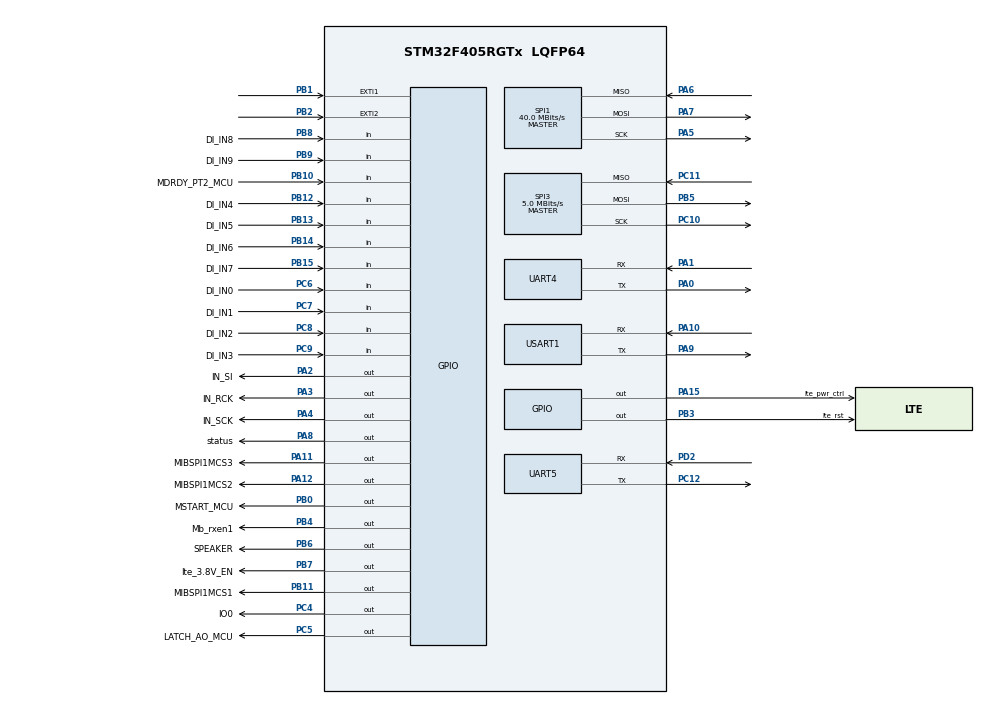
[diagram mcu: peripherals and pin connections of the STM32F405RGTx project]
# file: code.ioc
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Dma.Request0=UART4_RX
Dma.Request1=UART5_RX
Dma.Request2=USART1_RX
Dma.UART4_RX.0.Direction=DMA_PERIPH_TO_MEMORY
Dma.UART4_RX.0.FIFOMode=DMA_FIFOMODE_DISABLE
Dma.UART4_RX.0.Instance=DMA1_Stream2
Dma.UART4_RX.0.MemDataAlignment=DMA_MDATAALIGN_BYTE
Dma.UART4_RX.0.MemInc=DMA_MINC_ENABLE
Dma.UART4_RX.0.Mode=DMA_NORMAL
Dma.UART4_RX.0.PeriphDataAlignment=DMA_PDATAALIGN_BYTE
Dma.UART4_RX.0.PeriphInc=DMA_PINC_DISABLE
Dma.UART4_RX.0.Priority=DMA_PRIORITY_LOW
Dma.UART5_RX.1.Direction=DMA_PERIPH_TO_MEMORY
Dma.UART5_RX.1.FIFOMode=DMA_FIFOMODE_DISABLE
Dma.UART5_RX.1.Instance=DMA1_Stream0
Dma.UART5_RX.1.MemDataAlignment=DMA_MDATAALIGN_BYTE
Dma.UART5_RX.1.MemInc=DMA_MINC_ENABLE
Dma.UART5_RX.1.Mode=DMA_NORMAL
Dma.UART5_RX.1.PeriphDataAlignment=DMA_PDATAALIGN_BYTE
Dma.UART5_RX.1.PeriphInc=DMA_PINC_DISABLE
Dma.UART5_RX.1.Priority=DMA_PRIORITY_LOW
Dma.USART1_RX.2.Direction=DMA_PERIPH_TO_MEMORY
Dma.USART1_RX.2.FIFOMode=DMA_FIFOMODE_DISABLE
Dma.USART1_RX.2.Instance=DMA2_Stream2
Dma.USART1_RX.2.MemDataAlignment=DMA_MDATAALIGN_BYTE
Dma.USART1_RX.2.MemInc=DMA_MINC_ENABLE
Dma.USART1_RX.2.Mode=DMA_NORMAL
Dma.USART1_RX.2.PeriphDataAlignment=DMA_PDATAALIGN_BYTE
Dma.USART1_RX.2.PeriphInc=DMA_PINC_DISABLE
Dma.USART1_RX.2.Priority=DMA_PRIORITY_LOW
IWDG.Prescaler=IWDG_PRESCALER_256
IWDG.Reload=125
Mcu.Family=STM32F4
Mcu.Name=STM32F405RGTx
Mcu.Package=LQFP64
NVIC.DMA1_Stream0_IRQn=true\:0\:0\:false\:false\:true\:false\:true\:true
NVIC.DMA1_Stream2_IRQn=true\:0\:0\:false\:false\:true\:false\:true\:true
NVIC.DMA2_Stream2_IRQn=true\:0\:0\:false\:false\:true\:false\:true\:true
NVIC.EXTI1_IRQn=true\:0\:0\:false\:false\:true\:true\:true\:true
NVIC.EXTI2_IRQn=true\:0\:0\:false\:false\:true\:true\:true\:true
NVIC.PriorityGroup=NVIC_PRIORITYGROUP_4
NVIC.UART4_IRQn=true\:0\:0\:false\:false\:true\:true\:true\:true
NVIC.UART5_IRQn=true\:0\:0\:false\:false\:true\:true\:true\:true
NVIC.USART1_IRQn=true\:0\:0\:false\:false\:true\:true\:true\:true
PA0-WKUP.Mode=Asynchronous
PA0-WKUP.Signal=UART4_TX
PA1.Mode=Asynchronous
PA1.Signal=UART4_RX
PA10.Mode=Asynchronous
PA10.Signal=USART1_RX
PA11.GPIO_Label=MIBSPI1MCS3
PA11.Signal=GPIO_Output
PA12.GPIO_Label=MIBSPI1MCS2
PA12.Signal=GPIO_Output
PA13.Mode=Serial_Wire
PA13.Signal=SYS_JTMS-SWDIO
PA14.Mode=Serial_Wire
PA14.Signal=SYS_JTCK-SWCLK
PA15.GPIO_Label=lte_pwr_ctrl
PA15.Signal=GPIO_Output
PA2.GPIO_Label=IN_SI
PA2.Signal=GPIO_Output
PA3.GPIO_Label=IN_RCK
PA3.Signal=GPIO_Output
PA4.GPIO_Label=IN_SCK
PA4.Signal=GPIO_Output
PA5.Mode=Full_Duplex_Master
PA5.Signal=SPI1_SCK
PA6.Mode=Full_Duplex_Master
PA6.Signal=SPI1_MISO
PA7.Mode=Full_Duplex_Master
PA7.Signal=SPI1_MOSI
PA8.GPIO_Label=status
PA8.Signal=GPIO_Output
PA9.Mode=Asynchronous
PA9.Signal=USART1_TX
PB0.GPIO_Label=MSTART_MCU
PB0.Signal=GPIO_Output
PB1.GPIO_ModeDefaultEXTI=GPIO_MODE_IT_FALLING
PB1.GPIO_PuPd=GPIO_PULLUP
PB1.Signal=GPXTI1
PB10.GPIO_Label=MDRDY_PT2_MCU
PB10.Signal=GPIO_Input
PB11.GPIO_Label=MIBSPI1MCS1
PB11.GPIO_PuPd=GPIO_PULLUP
PB11.PinState=GPIO_PIN_SET
PB11.Signal=GPIO_Output
PB12.GPIO_Label=DI_IN4
PB12.Signal=GPIO_Input
PB13.GPIO_Label=DI_IN5
PB13.Signal=GPIO_Input
PB14.GPIO_Label=DI_IN6
PB14.Signal=GPIO_Input
PB15.GPIO_Label=DI_IN7
PB15.Signal=GPIO_Input
PB2.GPIO_ModeDefaultEXTI=GPIO_MODE_IT_FALLING
PB2.GPIO_PuPd=GPIO_PULLUP
PB2.Signal=GPXTI2
PB3.GPIO_Label=lte_rst
PB3.Signal=GPIO_Output
PB4.GPIO_Label=Mb_rxen1
PB4.Signal=GPIO_Output
PB5.Mode=Full_Duplex_Master
PB5.Signal=SPI3_MOSI
PB6.GPIO_Label=SPEAKER
PB6.Signal=GPIO_Output
PB7.GPIO_Label=lte_3.8V_EN
PB7.Signal=GPIO_Output
PB8.GPIO_Label=DI_IN8
PB8.Signal=GPIO_Input
PB9.GPIO_Label=DI_IN9
PB9.Signal=GPIO_Input
PC10.Mode=Full_Duplex_Master
PC10.Signal=SPI3_SCK
PC11.Mode=Full_Duplex_Master
PC11.Signal=SPI3_MISO
PC12.Mode=Asynchronous
PC12.Signal=UART5_TX
PC4.GPIO_Label=IO0
PC4.Signal=GPIO_Output
PC5.GPIO_Label=LATCH_AO_MCU
PC5.Signal=GPIO_Output
PC6.GPIO_Label=DI_IN0
PC6.Signal=GPIO_Input
PC7.GPIO_Label=DI_IN1
PC7.Signal=GPIO_Input
PC8.GPIO_Label=DI_IN2
PC8.Signal=GPIO_Input
PC9.GPIO_Label=DI_IN3
PC9.Signal=GPIO_Input
PD2.Mode=Asynchronous
PD2.Signal=UART5_RX
PH0-OSC_IN.Mode=HSE-External-Oscillator
PH0-OSC_IN.Signal=RCC_OSC_IN
PH1-OSC_OUT.Mode=HSE-External-Oscillator
PH1-OSC_OUT.Signal=RCC_OSC_OUT
ProjectManager.HeapSize=0x200
ProjectManager.StackSize=0x400
ProjectManager.TargetToolchain=MDK-ARM V5
RCC.48MHZClocksFreq_Value=40000000
RCC.AHBFreq_Value=80000000
RCC.APB1CLKDivider=RCC_HCLK_DIV2
RCC.APB1Freq_Value=40000000
RCC.APB1TimFreq_Value=80000000
RCC.APB2Freq_Value=80000000
RCC.APB2TimFreq_Value=80000000
RCC.CortexFreq_Value=80000000
RCC.HCLKFreq_Value=80000000
RCC.HSE_VALUE=8000000
RCC.HSI_VALUE=16000000
RCC.LSE_VALUE=32768
RCC.PLLM=4
RCC.PLLN=80
RCC.PLLSourceVirtual=RCC_PLLSOURCE_HSE
RCC.SYSCLKFreq_VALUE=80000000
RCC.SYSCLKSource=RCC_SYSCLKSOURCE_PLLCLK
RCC.VCOOutputFreq_Value=160000000
SPI1.BaudRatePrescaler=SPI_BAUDRATEPRESCALER_2
SPI1.CalculateBaudRate=40.0 MBits/s
SPI1.Direction=SPI_DIRECTION_2LINES
SPI1.Mode=SPI_MODE_MASTER
SPI1.VirtualType=VM_MASTER
SPI3.BaudRatePrescaler=SPI_BAUDRATEPRESCALER_8
SPI3.CalculateBaudRate=5.0 MBits/s
SPI3.Direction=SPI_DIRECTION_2LINES
SPI3.Mode=SPI_MODE_MASTER
SPI3.VirtualType=VM_MASTER
UART4.VirtualMode=Asynchronous
UART5.VirtualMode=Asynchronous
USART1.VirtualMode=VM_ASYNC
VP_IWDG_VS_IWDG.Mode=IWDG_Activate
board=custom

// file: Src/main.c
/* USER CODE BEGIN Header */
/**
  ******************************************************************************
  * @file           : main.c
  * @brief          : Main program body
  ******************************************************************************
  * @attention
  *
  * <h2><center>&copy; Copyright (c) 2023 STMicroelectronics.
  * All rights reserved.</center></h2>
  *
  * This software component is licensed by ST under BSD 3-Clause license,
  * the "License"; You may not use this file except in compliance with the
  * License. You may obtain a copy of the License at:
  *                        opensource.org/licenses/BSD-3-Clause
  *
  ******************************************************************************
  */
/* USER CODE END Header */
#include "main.h"

/* USER CODE BEGIN Includes */
#include "app.h"
#include "update.h"
#include "stdio.h"
/* USER CODE END Includes */

IWDG_HandleTypeDef hiwdg;

SPI_HandleTypeDef hspi1;
SPI_HandleTypeDef hspi3;

UART_HandleTypeDef huart4;
UART_HandleTypeDef huart5;
UART_HandleTypeDef huart1;
DMA_HandleTypeDef hdma_uart4_rx;
DMA_HandleTypeDef hdma_uart5_rx;
DMA_HandleTypeDef hdma_usart1_rx;

void SystemClock_Config(void);
static void MX_GPIO_Init(void);
static void MX_DMA_Init(void);
static void MX_SPI3_Init(void);
static void MX_UART4_Init(void);
static void MX_UART5_Init(void);
static void MX_USART1_UART_Init(void);
static void MX_SPI1_Init(void);
static void MX_IWDG_Init(void);

/* USER CODE BEGIN 0 */

extern UART_HandleTypeDef huart1;
struct __FILE
{
    int handle;
};
FILE __stdout;

int fputc(int ch, FILE *f)
{
    unsigned char tmp;
    tmp =(unsigned char )ch;

    HAL_UART_Transmit(&huart1, &tmp, 1, 500);

    return ch;
}
/* USER CODE END 0 */

int main(void)
{

  /* MCU Configuration--------------------------------------------------------*/

  /* Reset of all peripherals, Initializes the Flash interface and the Systick. */
  HAL_Init();

  /* Configure the system clock */
  SystemClock_Config();

  /* Initialize all configured peripherals */
  MX_GPIO_Init();
  MX_DMA_Init();
  MX_SPI3_Init();
  MX_UART4_Init();
  MX_UART5_Init();
  MX_USART1_UART_Init();
  MX_SPI1_Init();
  //MX_IWDG_Init();
  /* USER CODE BEGIN 2 */
  //hardware_init();
	HAL_Delay(3000);
	//MX_IWDG_Init();
	 //test();
	// Start_BootLoader();
  /* USER CODE END 2 */

  /* Infinite loop */
  while (1)
  {
//HAL_IWDG_Refresh(&hiwdg);
    /* USER CODE BEGIN 3 */
		Start_BootLoader();
  }
  /* USER CODE END 3 */
}

void SystemClock_Config(void)
{
  RCC_OscInitTypeDef RCC_OscInitStruct = {0};
  RCC_ClkInitTypeDef RCC_ClkInitStruct = {0};

  /** Configure the main internal regulator output voltage
  */
  __HAL_RCC_PWR_CLK_ENABLE();
  __HAL_PWR_VOLTAGESCALING_CONFIG(PWR_REGULATOR_VOLTAGE_SCALE1);

  /** Initializes the RCC Oscillators according to the specified parameters
  * in the RCC_OscInitTypeDef structure.
  */
  RCC_OscInitStruct.OscillatorType = RCC_OSCILLATORTYPE_HSI|RCC_OSCILLATORTYPE_LSI;
  RCC_OscInitStruct.HSIState = RCC_HSI_ON;
  RCC_OscInitStruct.HSICalibrationValue = RCC_HSICALIBRATION_DEFAULT;
  RCC_OscInitStruct.LSIState = RCC_LSI_ON;
  RCC_OscInitStruct.PLL.PLLState = RCC_PLL_ON;
  RCC_OscInitStruct.PLL.PLLSource = RCC_PLLSOURCE_HSI;
  RCC_OscInitStruct.PLL.PLLM = 8;
  RCC_OscInitStruct.PLL.PLLN = 120;
  RCC_OscInitStruct.PLL.PLLP = RCC_PLLP_DIV2;
  RCC_OscInitStruct.PLL.PLLQ = 4;
  if (HAL_RCC_OscConfig(&RCC_OscInitStruct) != HAL_OK)
  {
    Error_Handler();
  }

  /** Initializes the CPU, AHB and APB buses clocks
  */
  RCC_ClkInitStruct.ClockType = RCC_CLOCKTYPE_HCLK|RCC_CLOCKTYPE_SYSCLK
                              |RCC_CLOCKTYPE_PCLK1|RCC_CLOCKTYPE_PCLK2;
  RCC_ClkInitStruct.SYSCLKSource = RCC_SYSCLKSOURCE_PLLCLK;
  RCC_ClkInitStruct.AHBCLKDivider = RCC_SYSCLK_DIV1;
  RCC_ClkInitStruct.APB1CLKDivider = RCC_HCLK_DIV4;
  RCC_ClkInitStruct.APB2CLKDivider = RCC_HCLK_DIV2;

  if (HAL_RCC_ClockConfig(&RCC_ClkInitStruct, FLASH_LATENCY_3) != HAL_OK)
  {
    Error_Handler();
  }
}

static void MX_IWDG_Init(void)
{

  hiwdg.Instance = IWDG;
  hiwdg.Init.Prescaler = IWDG_PRESCALER_256;
  hiwdg.Init.Reload = 4095;
  if (HAL_IWDG_Init(&hiwdg) != HAL_OK)
  {
    Error_Handler();
  }

}

static void MX_SPI1_Init(void)
{

  /* SPI1 parameter configuration*/
  hspi1.Instance = SPI1;
  hspi1.Init.Mode = SPI_MODE_MASTER;
  hspi1.Init.Direction = SPI_DIRECTION_2LINES;
  hspi1.Init.DataSize = SPI_DATASIZE_8BIT;
  hspi1.Init.CLKPolarity = SPI_POLARITY_LOW;
  hspi1.Init.CLKPhase = SPI_PHASE_1EDGE;
  hspi1.Init.NSS = SPI_NSS_SOFT;
  hspi1.Init.BaudRatePrescaler = SPI_BAUDRATEPRESCALER_2;
  hspi1.Init.FirstBit = SPI_FIRSTBIT_MSB;
  hspi1.Init.TIMode = SPI_TIMODE_DISABLE;
  hspi1.Init.CRCCalculation = SPI_CRCCALCULATION_DISABLE;
  hspi1.Init.CRCPolynomial = 10;
  if (HAL_SPI_Init(&hspi1) != HAL_OK)
  {
    Error_Handler();
  }

}

static void MX_SPI3_Init(void)
{

  /* SPI3 parameter configuration*/
  hspi3.Instance = SPI3;
  hspi3.Init.Mode = SPI_MODE_MASTER;
  hspi3.Init.Direction = SPI_DIRECTION_2LINES;
  hspi3.Init.DataSize = SPI_DATASIZE_8BIT;
  hspi3.Init.CLKPolarity = SPI_POLARITY_LOW;
  hspi3.Init.CLKPhase = SPI_PHASE_1EDGE;
  hspi3.Init.NSS = SPI_NSS_SOFT;
  hspi3.Init.BaudRatePrescaler = SPI_BAUDRATEPRESCALER_8;
  hspi3.Init.FirstBit = SPI_FIRSTBIT_MSB;
  hspi3.Init.TIMode = SPI_TIMODE_DISABLE;
  hspi3.Init.CRCCalculation = SPI_CRCCALCULATION_DISABLE;
  hspi3.Init.CRCPolynomial = 10;
  if (HAL_SPI_Init(&hspi3) != HAL_OK)
  {
    Error_Handler();
  }

}

static void MX_UART4_Init(void)
{

  huart4.Instance = UART4;
  huart4.Init.BaudRate = 115200;
  huart4.Init.WordLength = UART_WORDLENGTH_8B;
  huart4.Init.StopBits = UART_STOPBITS_1;
  huart4.Init.Parity = UART_PARITY_NONE;
  huart4.Init.Mode = UART_MODE_TX_RX;
  huart4.Init.HwFlowCtl = UART_HWCONTROL_NONE;
  huart4.Init.OverSampling = UART_OVERSAMPLING_16;
  if (HAL_UART_Init(&huart4) != HAL_OK)
  {
    Error_Handler();
  }

}

static void MX_UART5_Init(void)
{

  huart5.Instance = UART5;
  huart5.Init.BaudRate = 115200;
  huart5.Init.WordLength = UART_WORDLENGTH_8B;
  huart5.Init.StopBits = UART_STOPBITS_1;
  huart5.Init.Parity = UART_PARITY_NONE;
  huart5.Init.Mode = UART_MODE_TX_RX;
  huart5.Init.HwFlowCtl = UART_HWCONTROL_NONE;
  huart5.Init.OverSampling = UART_OVERSAMPLING_16;
  if (HAL_UART_Init(&huart5) != HAL_OK)
  {
    Error_Handler();
  }

}

static void MX_USART1_UART_Init(void)
{

  huart1.Instance = USART1;
  huart1.Init.BaudRate = 115200;
  huart1.Init.WordLength = UART_WORDLENGTH_8B;
  huart1.Init.StopBits = UART_STOPBITS_1;
  huart1.Init.Parity = UART_PARITY_NONE;
  huart1.Init.Mode = UART_MODE_TX_RX;
  huart1.Init.HwFlowCtl = UART_HWCONTROL_NONE;
  huart1.Init.OverSampling = UART_OVERSAMPLING_16;
  if (HAL_UART_Init(&huart1) != HAL_OK)
  {
    Error_Handler();
  }

}

static void MX_DMA_Init(void)
{

  /* DMA controller clock enable */
  __HAL_RCC_DMA1_CLK_ENABLE();
  __HAL_RCC_DMA2_CLK_ENABLE();

  /* DMA interrupt init */
  /* DMA1_Stream0_IRQn interrupt configuration */
  HAL_NVIC_SetPriority(DMA1_Stream0_IRQn, 0, 0);
  HAL_NVIC_EnableIRQ(DMA1_Stream0_IRQn);
  /* DMA1_Stream2_IRQn interrupt configuration */
  HAL_NVIC_SetPriority(DMA1_Stream2_IRQn, 0, 0);
  HAL_NVIC_EnableIRQ(DMA1_Stream2_IRQn);
  /* DMA2_Stream2_IRQn interrupt configuration */
  HAL_NVIC_SetPriority(DMA2_Stream2_IRQn, 0, 0);
  HAL_NVIC_EnableIRQ(DMA2_Stream2_IRQn);

}

static void MX_GPIO_Init(void)
{
  GPIO_InitTypeDef GPIO_InitStruct = {0};

  /* GPIO Ports Clock Enable */
  __HAL_RCC_GPIOH_CLK_ENABLE();
  __HAL_RCC_GPIOA_CLK_ENABLE();
  __HAL_RCC_GPIOC_CLK_ENABLE();
  __HAL_RCC_GPIOB_CLK_ENABLE();
  __HAL_RCC_GPIOD_CLK_ENABLE();

  /*Configure GPIO pin Output Level */
  HAL_GPIO_WritePin(GPIOA, IN_SI_Pin|IN_RCK_Pin|IN_SCK_Pin|status_Pin
                          |MIBSPI1MCS3_Pin|MIBSPI1MCS2_Pin|lte_pwr_ctrl_Pin, GPIO_PIN_RESET);

  /*Configure GPIO pin Output Level */
  HAL_GPIO_WritePin(GPIOC, IO0_Pin|LATCH_AO_MCU_Pin, GPIO_PIN_RESET);

  /*Configure GPIO pin Output Level */
  HAL_GPIO_WritePin(GPIOB, MSTART_MCU_Pin|lte_rst_Pin|Mb_rxen1_Pin|SPEAKER_Pin
                          |lte_3_8V_EN_Pin, GPIO_PIN_RESET);

  /*Configure GPIO pin Output Level */
  HAL_GPIO_WritePin(MIBSPI1MCS1_GPIO_Port, MIBSPI1MCS1_Pin, GPIO_PIN_SET);

  /*Configure GPIO pins : IN_SI_Pin IN_RCK_Pin IN_SCK_Pin status_Pin
                           MIBSPI1MCS3_Pin MIBSPI1MCS2_Pin lte_pwr_ctrl_Pin */
  GPIO_InitStruct.Pin = IN_SI_Pin|IN_RCK_Pin|IN_SCK_Pin|status_Pin
                          |MIBSPI1MCS3_Pin|MIBSPI1MCS2_Pin|lte_pwr_ctrl_Pin;
  GPIO_InitStruct.Mode = GPIO_MODE_OUTPUT_PP;
  GPIO_InitStruct.Pull = GPIO_NOPULL;
  GPIO_InitStruct.Speed = GPIO_SPEED_FREQ_LOW;
  HAL_GPIO_Init(GPIOA, &GPIO_InitStruct);

  /*Configure GPIO pins : IO0_Pin LATCH_AO_MCU_Pin */
  GPIO_InitStruct.Pin = IO0_Pin|LATCH_AO_MCU_Pin;
  GPIO_InitStruct.Mode = GPIO_MODE_OUTPUT_PP;
  GPIO_InitStruct.Pull = GPIO_NOPULL;
  GPIO_InitStruct.Speed = GPIO_SPEED_FREQ_LOW;
  HAL_GPIO_Init(GPIOC, &GPIO_InitStruct);

  /*Configure GPIO pins : MSTART_MCU_Pin lte_rst_Pin Mb_rxen1_Pin SPEAKER_Pin
                           lte_3_8V_EN_Pin */
  GPIO_InitStruct.Pin = MSTART_MCU_Pin|lte_rst_Pin|Mb_rxen1_Pin|SPEAKER_Pin
                          |lte_3_8V_EN_Pin;
  GPIO_InitStruct.Mode = GPIO_MODE_OUTPUT_PP;
  GPIO_InitStruct.Pull = GPIO_NOPULL;
  GPIO_InitStruct.Speed = GPIO_SPEED_FREQ_LOW;
  HAL_GPIO_Init(GPIOB, &GPIO_InitStruct);

  /*Configure GPIO pins : PB1 PB2 */
  GPIO_InitStruct.Pin = GPIO_PIN_1|GPIO_PIN_2;
  GPIO_InitStruct.Mode = GPIO_MODE_IT_FALLING;
  GPIO_InitStruct.Pull = GPIO_PULLUP;
  HAL_GPIO_Init(GPIOB, &GPIO_InitStruct);

  /*Configure GPIO pins : MDRDY_PT2_MCU_Pin DI_IN4_Pin DI_IN5_Pin DI_IN6_Pin
                           DI_IN7_Pin DI_IN8_Pin DI_IN9_Pin */
  GPIO_InitStruct.Pin = MDRDY_PT2_MCU_Pin|DI_IN4_Pin|DI_IN5_Pin|DI_IN6_Pin
                          |DI_IN7_Pin|DI_IN8_Pin|DI_IN9_Pin;
  GPIO_InitStruct.Mode = GPIO_MODE_INPUT;
  GPIO_InitStruct.Pull = GPIO_NOPULL;
  HAL_GPIO_Init(GPIOB, &GPIO_InitStruct);

  /*Configure GPIO pin : MIBSPI1MCS1_Pin */
  GPIO_InitStruct.Pin = MIBSPI1MCS1_Pin;
  GPIO_InitStruct.Mode = GPIO_MODE_OUTPUT_PP;
  GPIO_InitStruct.Pull = GPIO_PULLUP;
  GPIO_InitStruct.Speed = GPIO_SPEED_FREQ_LOW;
  HAL_GPIO_Init(MIBSPI1MCS1_GPIO_Port, &GPIO_InitStruct);

  /*Configure GPIO pins : DI_IN0_Pin DI_IN1_Pin DI_IN2_Pin DI_IN3_Pin */
  GPIO_InitStruct.Pin = DI_IN0_Pin|DI_IN1_Pin|DI_IN2_Pin|DI_IN3_Pin;
  GPIO_InitStruct.Mode = GPIO_MODE_INPUT;
  GPIO_InitStruct.Pull = GPIO_NOPULL;
  HAL_GPIO_Init(GPIOC, &GPIO_InitStruct);

  /* EXTI interrupt init*/
  HAL_NVIC_SetPriority(EXTI1_IRQn, 0, 0);
  HAL_NVIC_EnableIRQ(EXTI1_IRQn);

  HAL_NVIC_SetPriority(EXTI2_IRQn, 0, 0);
  HAL_NVIC_EnableIRQ(EXTI2_IRQn);

}

void Error_Handler(void)
{
}
